VERSION 5.7 ;
BUSBITCHARS "[]" ;
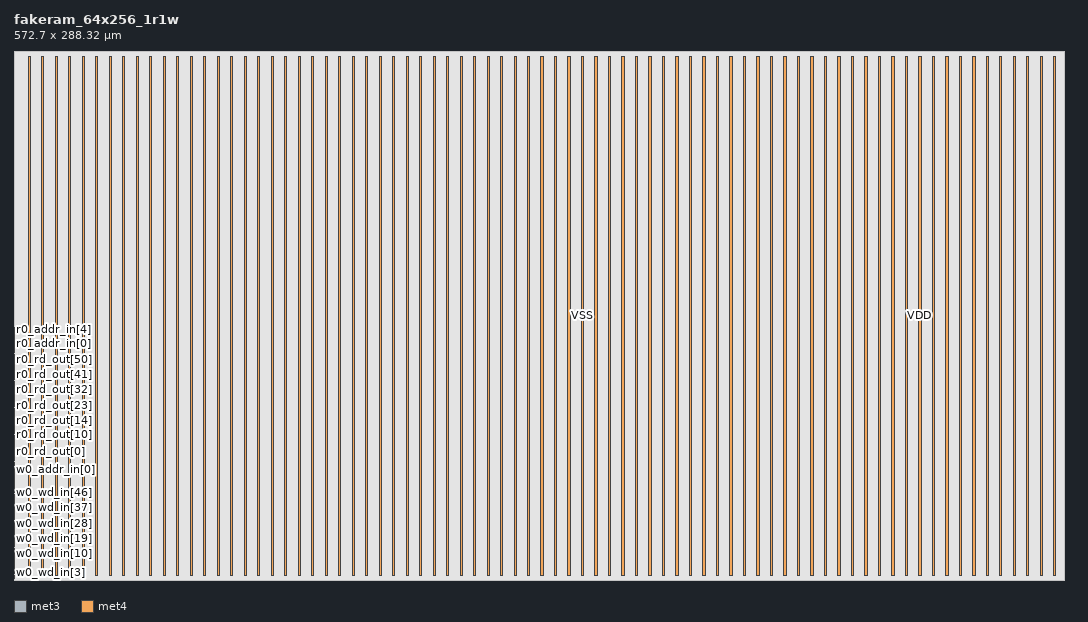
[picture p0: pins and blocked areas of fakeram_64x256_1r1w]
MACRO fakeram_64x256_1r1w
  FOREIGN fakeram_64x256_1r1w 0 0 ;
  SYMMETRY X Y R90 ;
  SIZE 572.700 BY 288.320 ;
  CLASS BLOCK ;
  PIN w0_wd_in[0]
    DIRECTION INPUT ;
    USE SIGNAL ;
    SHAPE ABUTMENT ;
    PORT
      LAYER met3 ;
      RECT 0.000 0.920 0.500 1.420 ;
    END
  END w0_wd_in[0]
  PIN w0_wd_in[1]
    DIRECTION INPUT ;
    USE SIGNAL ;
    SHAPE ABUTMENT ;
    PORT
      LAYER met3 ;
      RECT 0.000 1.840 0.500 2.340 ;
    END
  END w0_wd_in[1]
  PIN w0_wd_in[2]
    DIRECTION INPUT ;
    USE SIGNAL ;
    SHAPE ABUTMENT ;
    PORT
      LAYER met3 ;
      RECT 0.000 2.760 0.500 3.260 ;
    END
  END w0_wd_in[2]
  PIN w0_wd_in[3]
    DIRECTION INPUT ;
    USE SIGNAL ;
    SHAPE ABUTMENT ;
    PORT
      LAYER met3 ;
      RECT 0.000 3.680 0.500 4.180 ;
    END
  END w0_wd_in[3]
  PIN w0_wd_in[4]
    DIRECTION INPUT ;
    USE SIGNAL ;
    SHAPE ABUTMENT ;
    PORT
      LAYER met3 ;
      RECT 0.000 4.600 0.500 5.100 ;
    END
  END w0_wd_in[4]
  PIN w0_wd_in[5]
    DIRECTION INPUT ;
    USE SIGNAL ;
    SHAPE ABUTMENT ;
    PORT
      LAYER met3 ;
      RECT 0.000 5.520 0.500 6.020 ;
    END
  END w0_wd_in[5]
  PIN w0_wd_in[6]
    DIRECTION INPUT ;
    USE SIGNAL ;
    SHAPE ABUTMENT ;
    PORT
      LAYER met3 ;
      RECT 0.000 6.440 0.500 6.940 ;
    END
  END w0_wd_in[6]
  PIN w0_wd_in[7]
    DIRECTION INPUT ;
    USE SIGNAL ;
    SHAPE ABUTMENT ;
    PORT
      LAYER met3 ;
      RECT 0.000 7.360 0.500 7.860 ;
    END
  END w0_wd_in[7]
  PIN w0_wd_in[8]
    DIRECTION INPUT ;
    USE SIGNAL ;
    SHAPE ABUTMENT ;
    PORT
      LAYER met3 ;
      RECT 0.000 8.280 0.500 8.780 ;
    END
  END w0_wd_in[8]
  PIN w0_wd_in[9]
    DIRECTION INPUT ;
    USE SIGNAL ;
    SHAPE ABUTMENT ;
    PORT
      LAYER met3 ;
      RECT 0.000 9.200 0.500 9.700 ;
    END
  END w0_wd_in[9]
  PIN w0_wd_in[10]
    DIRECTION INPUT ;
    USE SIGNAL ;
    SHAPE ABUTMENT ;
    PORT
      LAYER met3 ;
      RECT 0.000 10.120 0.500 10.620 ;
    END
  END w0_wd_in[10]
  PIN w0_wd_in[11]
    DIRECTION INPUT ;
    USE SIGNAL ;
    SHAPE ABUTMENT ;
    PORT
      LAYER met3 ;
      RECT 0.000 11.040 0.500 11.540 ;
    END
  END w0_wd_in[11]
  PIN w0_wd_in[12]
    DIRECTION INPUT ;
    USE SIGNAL ;
    SHAPE ABUTMENT ;
    PORT
      LAYER met3 ;
      RECT 0.000 11.960 0.500 12.460 ;
    END
  END w0_wd_in[12]
  PIN w0_wd_in[13]
    DIRECTION INPUT ;
    USE SIGNAL ;
    SHAPE ABUTMENT ;
    PORT
      LAYER met3 ;
      RECT 0.000 12.880 0.500 13.380 ;
    END
  END w0_wd_in[13]
  PIN w0_wd_in[14]
    DIRECTION INPUT ;
    USE SIGNAL ;
    SHAPE ABUTMENT ;
    PORT
      LAYER met3 ;
      RECT 0.000 13.800 0.500 14.300 ;
    END
  END w0_wd_in[14]
  PIN w0_wd_in[15]
    DIRECTION INPUT ;
    USE SIGNAL ;
    SHAPE ABUTMENT ;
    PORT
      LAYER met3 ;
      RECT 0.000 14.720 0.500 15.220 ;
    END
  END w0_wd_in[15]
  PIN w0_wd_in[16]
    DIRECTION INPUT ;
    USE SIGNAL ;
    SHAPE ABUTMENT ;
    PORT
      LAYER met3 ;
      RECT 0.000 15.640 0.500 16.140 ;
    END
  END w0_wd_in[16]
  PIN w0_wd_in[17]
    DIRECTION INPUT ;
    USE SIGNAL ;
    SHAPE ABUTMENT ;
    PORT
      LAYER met3 ;
      RECT 0.000 16.560 0.500 17.060 ;
    END
  END w0_wd_in[17]
  PIN w0_wd_in[18]
    DIRECTION INPUT ;
    USE SIGNAL ;
    SHAPE ABUTMENT ;
    PORT
      LAYER met3 ;
      RECT 0.000 17.480 0.500 17.980 ;
    END
  END w0_wd_in[18]
  PIN w0_wd_in[19]
    DIRECTION INPUT ;
    USE SIGNAL ;
    SHAPE ABUTMENT ;
    PORT
      LAYER met3 ;
      RECT 0.000 18.400 0.500 18.900 ;
    END
  END w0_wd_in[19]
  PIN w0_wd_in[20]
    DIRECTION INPUT ;
    USE SIGNAL ;
    SHAPE ABUTMENT ;
    PORT
      LAYER met3 ;
      RECT 0.000 19.320 0.500 19.820 ;
    END
  END w0_wd_in[20]
  PIN w0_wd_in[21]
    DIRECTION INPUT ;
    USE SIGNAL ;
    SHAPE ABUTMENT ;
    PORT
      LAYER met3 ;
      RECT 0.000 20.240 0.500 20.740 ;
    END
  END w0_wd_in[21]
  PIN w0_wd_in[22]
    DIRECTION INPUT ;
    USE SIGNAL ;
    SHAPE ABUTMENT ;
    PORT
      LAYER met3 ;
      RECT 0.000 21.160 0.500 21.660 ;
    END
  END w0_wd_in[22]
  PIN w0_wd_in[23]
    DIRECTION INPUT ;
    USE SIGNAL ;
    SHAPE ABUTMENT ;
    PORT
      LAYER met3 ;
      RECT 0.000 22.080 0.500 22.580 ;
    END
  END w0_wd_in[23]
  PIN w0_wd_in[24]
    DIRECTION INPUT ;
    USE SIGNAL ;
    SHAPE ABUTMENT ;
    PORT
      LAYER met3 ;
      RECT 0.000 23.000 0.500 23.500 ;
    END
  END w0_wd_in[24]
  PIN w0_wd_in[25]
    DIRECTION INPUT ;
    USE SIGNAL ;
    SHAPE ABUTMENT ;
    PORT
      LAYER met3 ;
      RECT 0.000 23.920 0.500 24.420 ;
    END
  END w0_wd_in[25]
  PIN w0_wd_in[26]
    DIRECTION INPUT ;
    USE SIGNAL ;
    SHAPE ABUTMENT ;
    PORT
      LAYER met3 ;
      RECT 0.000 24.840 0.500 25.340 ;
    END
  END w0_wd_in[26]
  PIN w0_wd_in[27]
    DIRECTION INPUT ;
    USE SIGNAL ;
    SHAPE ABUTMENT ;
    PORT
      LAYER met3 ;
      RECT 0.000 25.760 0.500 26.260 ;
    END
  END w0_wd_in[27]
  PIN w0_wd_in[28]
    DIRECTION INPUT ;
    USE SIGNAL ;
    SHAPE ABUTMENT ;
    PORT
      LAYER met3 ;
      RECT 0.000 26.680 0.500 27.180 ;
    END
  END w0_wd_in[28]
  PIN w0_wd_in[29]
    DIRECTION INPUT ;
    USE SIGNAL ;
    SHAPE ABUTMENT ;
    PORT
      LAYER met3 ;
      RECT 0.000 27.600 0.500 28.100 ;
    END
  END w0_wd_in[29]
  PIN w0_wd_in[30]
    DIRECTION INPUT ;
    USE SIGNAL ;
    SHAPE ABUTMENT ;
    PORT
      LAYER met3 ;
      RECT 0.000 28.520 0.500 29.020 ;
    END
  END w0_wd_in[30]
  PIN w0_wd_in[31]
    DIRECTION INPUT ;
    USE SIGNAL ;
    SHAPE ABUTMENT ;
    PORT
      LAYER met3 ;
      RECT 0.000 29.440 0.500 29.940 ;
    END
  END w0_wd_in[31]
  PIN w0_wd_in[32]
    DIRECTION INPUT ;
    USE SIGNAL ;
    SHAPE ABUTMENT ;
    PORT
      LAYER met3 ;
      RECT 0.000 30.360 0.500 30.860 ;
    END
  END w0_wd_in[32]
  PIN w0_wd_in[33]
    DIRECTION INPUT ;
    USE SIGNAL ;
    SHAPE ABUTMENT ;
    PORT
      LAYER met3 ;
      RECT 0.000 31.280 0.500 31.780 ;
    END
  END w0_wd_in[33]
  PIN w0_wd_in[34]
    DIRECTION INPUT ;
    USE SIGNAL ;
    SHAPE ABUTMENT ;
    PORT
      LAYER met3 ;
      RECT 0.000 32.200 0.500 32.700 ;
    END
  END w0_wd_in[34]
  PIN w0_wd_in[35]
    DIRECTION INPUT ;
    USE SIGNAL ;
    SHAPE ABUTMENT ;
    PORT
      LAYER met3 ;
      RECT 0.000 33.120 0.500 33.620 ;
    END
  END w0_wd_in[35]
  PIN w0_wd_in[36]
    DIRECTION INPUT ;
    USE SIGNAL ;
    SHAPE ABUTMENT ;
    PORT
      LAYER met3 ;
      RECT 0.000 34.040 0.500 34.540 ;
    END
  END w0_wd_in[36]
  PIN w0_wd_in[37]
    DIRECTION INPUT ;
    USE SIGNAL ;
    SHAPE ABUTMENT ;
    PORT
      LAYER met3 ;
      RECT 0.000 34.960 0.500 35.460 ;
    END
  END w0_wd_in[37]
  PIN w0_wd_in[38]
    DIRECTION INPUT ;
    USE SIGNAL ;
    SHAPE ABUTMENT ;
    PORT
      LAYER met3 ;
      RECT 0.000 35.880 0.500 36.380 ;
    END
  END w0_wd_in[38]
  PIN w0_wd_in[39]
    DIRECTION INPUT ;
    USE SIGNAL ;
    SHAPE ABUTMENT ;
    PORT
      LAYER met3 ;
      RECT 0.000 36.800 0.500 37.300 ;
    END
  END w0_wd_in[39]
  PIN w0_wd_in[40]
    DIRECTION INPUT ;
    USE SIGNAL ;
    SHAPE ABUTMENT ;
    PORT
      LAYER met3 ;
      RECT 0.000 37.720 0.500 38.220 ;
    END
  END w0_wd_in[40]
  PIN w0_wd_in[41]
    DIRECTION INPUT ;
    USE SIGNAL ;
    SHAPE ABUTMENT ;
    PORT
      LAYER met3 ;
      RECT 0.000 38.640 0.500 39.140 ;
    END
  END w0_wd_in[41]
  PIN w0_wd_in[42]
    DIRECTION INPUT ;
    USE SIGNAL ;
    SHAPE ABUTMENT ;
    PORT
      LAYER met3 ;
      RECT 0.000 39.560 0.500 40.060 ;
    END
  END w0_wd_in[42]
  PIN w0_wd_in[43]
    DIRECTION INPUT ;
    USE SIGNAL ;
    SHAPE ABUTMENT ;
    PORT
      LAYER met3 ;
      RECT 0.000 40.480 0.500 40.980 ;
    END
  END w0_wd_in[43]
  PIN w0_wd_in[44]
    DIRECTION INPUT ;
    USE SIGNAL ;
    SHAPE ABUTMENT ;
    PORT
      LAYER met3 ;
      RECT 0.000 41.400 0.500 41.900 ;
    END
  END w0_wd_in[44]
  PIN w0_wd_in[45]
    DIRECTION INPUT ;
    USE SIGNAL ;
    SHAPE ABUTMENT ;
    PORT
      LAYER met3 ;
      RECT 0.000 42.320 0.500 42.820 ;
    END
  END w0_wd_in[45]
  PIN w0_wd_in[46]
    DIRECTION INPUT ;
    USE SIGNAL ;
    SHAPE ABUTMENT ;
    PORT
      LAYER met3 ;
      RECT 0.000 43.240 0.500 43.740 ;
    END
  END w0_wd_in[46]
  PIN w0_wd_in[47]
    DIRECTION INPUT ;
    USE SIGNAL ;
    SHAPE ABUTMENT ;
    PORT
      LAYER met3 ;
      RECT 0.000 44.160 0.500 44.660 ;
    END
  END w0_wd_in[47]
  PIN w0_wd_in[48]
    DIRECTION INPUT ;
    USE SIGNAL ;
    SHAPE ABUTMENT ;
    PORT
      LAYER met3 ;
      RECT 0.000 45.080 0.500 45.580 ;
    END
  END w0_wd_in[48]
  PIN w0_wd_in[49]
    DIRECTION INPUT ;
    USE SIGNAL ;
    SHAPE ABUTMENT ;
    PORT
      LAYER met3 ;
      RECT 0.000 46.000 0.500 46.500 ;
    END
  END w0_wd_in[49]
  PIN w0_wd_in[50]
    DIRECTION INPUT ;
    USE SIGNAL ;
    SHAPE ABUTMENT ;
    PORT
      LAYER met3 ;
      RECT 0.000 46.920 0.500 47.420 ;
    END
  END w0_wd_in[50]
  PIN w0_wd_in[51]
    DIRECTION INPUT ;
    USE SIGNAL ;
    SHAPE ABUTMENT ;
    PORT
      LAYER met3 ;
      RECT 0.000 47.840 0.500 48.340 ;
    END
  END w0_wd_in[51]
  PIN w0_wd_in[52]
    DIRECTION INPUT ;
    USE SIGNAL ;
    SHAPE ABUTMENT ;
    PORT
      LAYER met3 ;
      RECT 0.000 48.760 0.500 49.260 ;
    END
  END w0_wd_in[52]
  PIN w0_wd_in[53]
    DIRECTION INPUT ;
    USE SIGNAL ;
    SHAPE ABUTMENT ;
    PORT
      LAYER met3 ;
      RECT 0.000 49.680 0.500 50.180 ;
    END
  END w0_wd_in[53]
  PIN w0_wd_in[54]
    DIRECTION INPUT ;
    USE SIGNAL ;
    SHAPE ABUTMENT ;
    PORT
      LAYER met3 ;
      RECT 0.000 50.600 0.500 51.100 ;
    END
  END w0_wd_in[54]
  PIN w0_wd_in[55]
    DIRECTION INPUT ;
    USE SIGNAL ;
    SHAPE ABUTMENT ;
    PORT
      LAYER met3 ;
      RECT 0.000 51.520 0.500 52.020 ;
    END
  END w0_wd_in[55]
  PIN w0_wd_in[56]
    DIRECTION INPUT ;
    USE SIGNAL ;
    SHAPE ABUTMENT ;
    PORT
      LAYER met3 ;
      RECT 0.000 52.440 0.500 52.940 ;
    END
  END w0_wd_in[56]
  PIN w0_wd_in[57]
    DIRECTION INPUT ;
    USE SIGNAL ;
    SHAPE ABUTMENT ;
    PORT
      LAYER met3 ;
      RECT 0.000 53.360 0.500 53.860 ;
    END
  END w0_wd_in[57]
  PIN w0_wd_in[58]
    DIRECTION INPUT ;
    USE SIGNAL ;
    SHAPE ABUTMENT ;
    PORT
      LAYER met3 ;
      RECT 0.000 54.280 0.500 54.780 ;
    END
  END w0_wd_in[58]
  PIN w0_wd_in[59]
    DIRECTION INPUT ;
    USE SIGNAL ;
    SHAPE ABUTMENT ;
    PORT
      LAYER met3 ;
      RECT 0.000 55.200 0.500 55.700 ;
    END
  END w0_wd_in[59]
  PIN w0_wd_in[60]
    DIRECTION INPUT ;
    USE SIGNAL ;
    SHAPE ABUTMENT ;
    PORT
      LAYER met3 ;
      RECT 0.000 56.120 0.500 56.620 ;
    END
  END w0_wd_in[60]
  PIN w0_wd_in[61]
    DIRECTION INPUT ;
    USE SIGNAL ;
    SHAPE ABUTMENT ;
    PORT
      LAYER met3 ;
      RECT 0.000 57.040 0.500 57.540 ;
    END
  END w0_wd_in[61]
  PIN w0_wd_in[62]
    DIRECTION INPUT ;
    USE SIGNAL ;
    SHAPE ABUTMENT ;
    PORT
      LAYER met3 ;
      RECT 0.000 57.960 0.500 58.460 ;
    END
  END w0_wd_in[62]
  PIN w0_wd_in[63]
    DIRECTION INPUT ;
    USE SIGNAL ;
    SHAPE ABUTMENT ;
    PORT
      LAYER met3 ;
      RECT 0.000 58.880 0.500 59.380 ;
    END
  END w0_wd_in[63]
  PIN w0_addr_in[0]
    DIRECTION INPUT ;
    USE SIGNAL ;
    SHAPE ABUTMENT ;
    PORT
      LAYER met3 ;
      RECT 0.000 59.800 0.500 60.300 ;
    END
  END w0_addr_in[0]
  PIN w0_addr_in[1]
    DIRECTION INPUT ;
    USE SIGNAL ;
    SHAPE ABUTMENT ;
    PORT
      LAYER met3 ;
      RECT 0.000 60.720 0.500 61.220 ;
    END
  END w0_addr_in[1]
  PIN w0_addr_in[2]
    DIRECTION INPUT ;
    USE SIGNAL ;
    SHAPE ABUTMENT ;
    PORT
      LAYER met3 ;
      RECT 0.000 61.640 0.500 62.140 ;
    END
  END w0_addr_in[2]
  PIN w0_addr_in[3]
    DIRECTION INPUT ;
    USE SIGNAL ;
    SHAPE ABUTMENT ;
    PORT
      LAYER met3 ;
      RECT 0.000 62.560 0.500 63.060 ;
    END
  END w0_addr_in[3]
  PIN w0_addr_in[4]
    DIRECTION INPUT ;
    USE SIGNAL ;
    SHAPE ABUTMENT ;
    PORT
      LAYER met3 ;
      RECT 0.000 63.480 0.500 63.980 ;
    END
  END w0_addr_in[4]
  PIN w0_addr_in[5]
    DIRECTION INPUT ;
    USE SIGNAL ;
    SHAPE ABUTMENT ;
    PORT
      LAYER met3 ;
      RECT 0.000 64.400 0.500 64.900 ;
    END
  END w0_addr_in[5]
  PIN w0_addr_in[6]
    DIRECTION INPUT ;
    USE SIGNAL ;
    SHAPE ABUTMENT ;
    PORT
      LAYER met3 ;
      RECT 0.000 65.320 0.500 65.820 ;
    END
  END w0_addr_in[6]
  PIN w0_addr_in[7]
    DIRECTION INPUT ;
    USE SIGNAL ;
    SHAPE ABUTMENT ;
    PORT
      LAYER met3 ;
      RECT 0.000 66.240 0.500 66.740 ;
    END
  END w0_addr_in[7]
  PIN w0_clk
    DIRECTION INPUT ;
    USE SIGNAL ;
    SHAPE ABUTMENT ;
    PORT
      LAYER met3 ;
      RECT 0.000 67.160 0.500 67.660 ;
    END
  END w0_clk
  PIN w0_ce_in
    DIRECTION INPUT ;
    USE SIGNAL ;
    SHAPE ABUTMENT ;
    PORT
      LAYER met3 ;
      RECT 0.000 68.080 0.500 68.580 ;
    END
  END w0_ce_in
  PIN w0_we_in
    DIRECTION INPUT ;
    USE SIGNAL ;
    SHAPE ABUTMENT ;
    PORT
      LAYER met3 ;
      RECT 0.000 69.000 0.500 69.500 ;
    END
  END w0_we_in
  PIN r0_rd_out[0]
    DIRECTION OUTPUT ;
    USE SIGNAL ;
    SHAPE ABUTMENT ;
    PORT
      LAYER met3 ;
      RECT 0.000 69.920 0.500 70.420 ;
    END
  END r0_rd_out[0]
  PIN r0_rd_out[1]
    DIRECTION OUTPUT ;
    USE SIGNAL ;
    SHAPE ABUTMENT ;
    PORT
      LAYER met3 ;
      RECT 0.000 70.840 0.500 71.340 ;
    END
  END r0_rd_out[1]
  PIN r0_rd_out[2]
    DIRECTION OUTPUT ;
    USE SIGNAL ;
    SHAPE ABUTMENT ;
    PORT
      LAYER met3 ;
      RECT 0.000 71.760 0.500 72.260 ;
    END
  END r0_rd_out[2]
  PIN r0_rd_out[3]
    DIRECTION OUTPUT ;
    USE SIGNAL ;
    SHAPE ABUTMENT ;
    PORT
      LAYER met3 ;
      RECT 0.000 72.680 0.500 73.180 ;
    END
  END r0_rd_out[3]
  PIN r0_rd_out[4]
    DIRECTION OUTPUT ;
    USE SIGNAL ;
    SHAPE ABUTMENT ;
    PORT
      LAYER met3 ;
      RECT 0.000 73.600 0.500 74.100 ;
    END
  END r0_rd_out[4]
  PIN r0_rd_out[5]
    DIRECTION OUTPUT ;
    USE SIGNAL ;
    SHAPE ABUTMENT ;
    PORT
      LAYER met3 ;
      RECT 0.000 74.520 0.500 75.020 ;
    END
  END r0_rd_out[5]
  PIN r0_rd_out[6]
    DIRECTION OUTPUT ;
    USE SIGNAL ;
    SHAPE ABUTMENT ;
    PORT
      LAYER met3 ;
      RECT 0.000 75.440 0.500 75.940 ;
    END
  END r0_rd_out[6]
  PIN r0_rd_out[7]
    DIRECTION OUTPUT ;
    USE SIGNAL ;
    SHAPE ABUTMENT ;
    PORT
      LAYER met3 ;
      RECT 0.000 76.360 0.500 76.860 ;
    END
  END r0_rd_out[7]
  PIN r0_rd_out[8]
    DIRECTION OUTPUT ;
    USE SIGNAL ;
    SHAPE ABUTMENT ;
    PORT
      LAYER met3 ;
      RECT 0.000 77.280 0.500 77.780 ;
    END
  END r0_rd_out[8]
  PIN r0_rd_out[9]
    DIRECTION OUTPUT ;
    USE SIGNAL ;
    SHAPE ABUTMENT ;
    PORT
      LAYER met3 ;
      RECT 0.000 78.200 0.500 78.700 ;
    END
  END r0_rd_out[9]
  PIN r0_rd_out[10]
    DIRECTION OUTPUT ;
    USE SIGNAL ;
    SHAPE ABUTMENT ;
    PORT
      LAYER met3 ;
      RECT 0.000 79.120 0.500 79.620 ;
    END
  END r0_rd_out[10]
  PIN r0_rd_out[11]
    DIRECTION OUTPUT ;
    USE SIGNAL ;
    SHAPE ABUTMENT ;
    PORT
      LAYER met3 ;
      RECT 0.000 80.040 0.500 80.540 ;
    END
  END r0_rd_out[11]
  PIN r0_rd_out[12]
    DIRECTION OUTPUT ;
    USE SIGNAL ;
    SHAPE ABUTMENT ;
    PORT
      LAYER met3 ;
      RECT 0.000 80.960 0.500 81.460 ;
    END
  END r0_rd_out[12]
  PIN r0_rd_out[13]
    DIRECTION OUTPUT ;
    USE SIGNAL ;
    SHAPE ABUTMENT ;
    PORT
      LAYER met3 ;
      RECT 0.000 81.880 0.500 82.380 ;
    END
  END r0_rd_out[13]
  PIN r0_rd_out[14]
    DIRECTION OUTPUT ;
    USE SIGNAL ;
    SHAPE ABUTMENT ;
    PORT
      LAYER met3 ;
      RECT 0.000 82.800 0.500 83.300 ;
    END
  END r0_rd_out[14]
  PIN r0_rd_out[15]
    DIRECTION OUTPUT ;
    USE SIGNAL ;
    SHAPE ABUTMENT ;
    PORT
      LAYER met3 ;
      RECT 0.000 83.720 0.500 84.220 ;
    END
  END r0_rd_out[15]
  PIN r0_rd_out[16]
    DIRECTION OUTPUT ;
    USE SIGNAL ;
    SHAPE ABUTMENT ;
    PORT
      LAYER met3 ;
      RECT 0.000 84.640 0.500 85.140 ;
    END
  END r0_rd_out[16]
  PIN r0_rd_out[17]
    DIRECTION OUTPUT ;
    USE SIGNAL ;
    SHAPE ABUTMENT ;
    PORT
      LAYER met3 ;
      RECT 0.000 85.560 0.500 86.060 ;
    END
  END r0_rd_out[17]
  PIN r0_rd_out[18]
    DIRECTION OUTPUT ;
    USE SIGNAL ;
    SHAPE ABUTMENT ;
    PORT
      LAYER met3 ;
      RECT 0.000 86.480 0.500 86.980 ;
    END
  END r0_rd_out[18]
  PIN r0_rd_out[19]
    DIRECTION OUTPUT ;
    USE SIGNAL ;
    SHAPE ABUTMENT ;
    PORT
      LAYER met3 ;
      RECT 0.000 87.400 0.500 87.900 ;
    END
  END r0_rd_out[19]
  PIN r0_rd_out[20]
    DIRECTION OUTPUT ;
    USE SIGNAL ;
    SHAPE ABUTMENT ;
    PORT
      LAYER met3 ;
      RECT 0.000 88.320 0.500 88.820 ;
    END
  END r0_rd_out[20]
  PIN r0_rd_out[21]
    DIRECTION OUTPUT ;
    USE SIGNAL ;
    SHAPE ABUTMENT ;
    PORT
      LAYER met3 ;
      RECT 0.000 89.240 0.500 89.740 ;
    END
  END r0_rd_out[21]
  PIN r0_rd_out[22]
    DIRECTION OUTPUT ;
    USE SIGNAL ;
    SHAPE ABUTMENT ;
    PORT
      LAYER met3 ;
      RECT 0.000 90.160 0.500 90.660 ;
    END
  END r0_rd_out[22]
  PIN r0_rd_out[23]
    DIRECTION OUTPUT ;
    USE SIGNAL ;
    SHAPE ABUTMENT ;
    PORT
      LAYER met3 ;
      RECT 0.000 91.080 0.500 91.580 ;
    END
  END r0_rd_out[23]
  PIN r0_rd_out[24]
    DIRECTION OUTPUT ;
    USE SIGNAL ;
    SHAPE ABUTMENT ;
    PORT
      LAYER met3 ;
      RECT 0.000 92.000 0.500 92.500 ;
    END
  END r0_rd_out[24]
  PIN r0_rd_out[25]
    DIRECTION OUTPUT ;
    USE SIGNAL ;
    SHAPE ABUTMENT ;
    PORT
      LAYER met3 ;
      RECT 0.000 92.920 0.500 93.420 ;
    END
  END r0_rd_out[25]
  PIN r0_rd_out[26]
    DIRECTION OUTPUT ;
    USE SIGNAL ;
    SHAPE ABUTMENT ;
    PORT
      LAYER met3 ;
      RECT 0.000 93.840 0.500 94.340 ;
    END
  END r0_rd_out[26]
  PIN r0_rd_out[27]
    DIRECTION OUTPUT ;
    USE SIGNAL ;
    SHAPE ABUTMENT ;
    PORT
      LAYER met3 ;
      RECT 0.000 94.760 0.500 95.260 ;
    END
  END r0_rd_out[27]
  PIN r0_rd_out[28]
    DIRECTION OUTPUT ;
    USE SIGNAL ;
    SHAPE ABUTMENT ;
    PORT
      LAYER met3 ;
      RECT 0.000 95.680 0.500 96.180 ;
    END
  END r0_rd_out[28]
  PIN r0_rd_out[29]
    DIRECTION OUTPUT ;
    USE SIGNAL ;
    SHAPE ABUTMENT ;
    PORT
      LAYER met3 ;
      RECT 0.000 96.600 0.500 97.100 ;
    END
  END r0_rd_out[29]
  PIN r0_rd_out[30]
    DIRECTION OUTPUT ;
    USE SIGNAL ;
    SHAPE ABUTMENT ;
    PORT
      LAYER met3 ;
      RECT 0.000 97.520 0.500 98.020 ;
    END
  END r0_rd_out[30]
  PIN r0_rd_out[31]
    DIRECTION OUTPUT ;
    USE SIGNAL ;
    SHAPE ABUTMENT ;
    PORT
      LAYER met3 ;
      RECT 0.000 98.440 0.500 98.940 ;
    END
  END r0_rd_out[31]
  PIN r0_rd_out[32]
    DIRECTION OUTPUT ;
    USE SIGNAL ;
    SHAPE ABUTMENT ;
    PORT
      LAYER met3 ;
      RECT 0.000 99.360 0.500 99.860 ;
    END
  END r0_rd_out[32]
  PIN r0_rd_out[33]
    DIRECTION OUTPUT ;
    USE SIGNAL ;
    SHAPE ABUTMENT ;
    PORT
      LAYER met3 ;
      RECT 0.000 100.280 0.500 100.780 ;
    END
  END r0_rd_out[33]
  PIN r0_rd_out[34]
    DIRECTION OUTPUT ;
    USE SIGNAL ;
    SHAPE ABUTMENT ;
    PORT
      LAYER met3 ;
      RECT 0.000 101.200 0.500 101.700 ;
    END
  END r0_rd_out[34]
  PIN r0_rd_out[35]
    DIRECTION OUTPUT ;
    USE SIGNAL ;
    SHAPE ABUTMENT ;
    PORT
      LAYER met3 ;
      RECT 0.000 102.120 0.500 102.620 ;
    END
  END r0_rd_out[35]
  PIN r0_rd_out[36]
    DIRECTION OUTPUT ;
    USE SIGNAL ;
    SHAPE ABUTMENT ;
    PORT
      LAYER met3 ;
      RECT 0.000 103.040 0.500 103.540 ;
    END
  END r0_rd_out[36]
  PIN r0_rd_out[37]
    DIRECTION OUTPUT ;
    USE SIGNAL ;
    SHAPE ABUTMENT ;
    PORT
      LAYER met3 ;
      RECT 0.000 103.960 0.500 104.460 ;
    END
  END r0_rd_out[37]
  PIN r0_rd_out[38]
    DIRECTION OUTPUT ;
    USE SIGNAL ;
    SHAPE ABUTMENT ;
    PORT
      LAYER met3 ;
      RECT 0.000 104.880 0.500 105.380 ;
    END
  END r0_rd_out[38]
  PIN r0_rd_out[39]
    DIRECTION OUTPUT ;
    USE SIGNAL ;
    SHAPE ABUTMENT ;
    PORT
      LAYER met3 ;
      RECT 0.000 105.800 0.500 106.300 ;
    END
  END r0_rd_out[39]
  PIN r0_rd_out[40]
    DIRECTION OUTPUT ;
    USE SIGNAL ;
    SHAPE ABUTMENT ;
    PORT
      LAYER met3 ;
      RECT 0.000 106.720 0.500 107.220 ;
    END
  END r0_rd_out[40]
  PIN r0_rd_out[41]
    DIRECTION OUTPUT ;
    USE SIGNAL ;
    SHAPE ABUTMENT ;
    PORT
      LAYER met3 ;
      RECT 0.000 107.640 0.500 108.140 ;
    END
  END r0_rd_out[41]
  PIN r0_rd_out[42]
    DIRECTION OUTPUT ;
    USE SIGNAL ;
    SHAPE ABUTMENT ;
    PORT
      LAYER met3 ;
      RECT 0.000 108.560 0.500 109.060 ;
    END
  END r0_rd_out[42]
  PIN r0_rd_out[43]
    DIRECTION OUTPUT ;
    USE SIGNAL ;
    SHAPE ABUTMENT ;
    PORT
      LAYER met3 ;
      RECT 0.000 109.480 0.500 109.980 ;
    END
  END r0_rd_out[43]
  PIN r0_rd_out[44]
    DIRECTION OUTPUT ;
    USE SIGNAL ;
    SHAPE ABUTMENT ;
    PORT
      LAYER met3 ;
      RECT 0.000 110.400 0.500 110.900 ;
    END
  END r0_rd_out[44]
  PIN r0_rd_out[45]
    DIRECTION OUTPUT ;
    USE SIGNAL ;
    SHAPE ABUTMENT ;
    PORT
      LAYER met3 ;
      RECT 0.000 111.320 0.500 111.820 ;
    END
  END r0_rd_out[45]
  PIN r0_rd_out[46]
    DIRECTION OUTPUT ;
    USE SIGNAL ;
    SHAPE ABUTMENT ;
    PORT
      LAYER met3 ;
      RECT 0.000 112.240 0.500 112.740 ;
    END
  END r0_rd_out[46]
  PIN r0_rd_out[47]
    DIRECTION OUTPUT ;
    USE SIGNAL ;
    SHAPE ABUTMENT ;
    PORT
      LAYER met3 ;
      RECT 0.000 113.160 0.500 113.660 ;
    END
  END r0_rd_out[47]
  PIN r0_rd_out[48]
    DIRECTION OUTPUT ;
    USE SIGNAL ;
    SHAPE ABUTMENT ;
    PORT
      LAYER met3 ;
      RECT 0.000 114.080 0.500 114.580 ;
    END
  END r0_rd_out[48]
  PIN r0_rd_out[49]
    DIRECTION OUTPUT ;
    USE SIGNAL ;
    SHAPE ABUTMENT ;
    PORT
      LAYER met3 ;
      RECT 0.000 115.000 0.500 115.500 ;
    END
  END r0_rd_out[49]
  PIN r0_rd_out[50]
    DIRECTION OUTPUT ;
    USE SIGNAL ;
    SHAPE ABUTMENT ;
    PORT
      LAYER met3 ;
      RECT 0.000 115.920 0.500 116.420 ;
    END
  END r0_rd_out[50]
  PIN r0_rd_out[51]
    DIRECTION OUTPUT ;
    USE SIGNAL ;
    SHAPE ABUTMENT ;
    PORT
      LAYER met3 ;
      RECT 0.000 116.840 0.500 117.340 ;
    END
  END r0_rd_out[51]
  PIN r0_rd_out[52]
    DIRECTION OUTPUT ;
    USE SIGNAL ;
    SHAPE ABUTMENT ;
    PORT
      LAYER met3 ;
      RECT 0.000 117.760 0.500 118.260 ;
    END
  END r0_rd_out[52]
  PIN r0_rd_out[53]
    DIRECTION OUTPUT ;
    USE SIGNAL ;
    SHAPE ABUTMENT ;
    PORT
      LAYER met3 ;
      RECT 0.000 118.680 0.500 119.180 ;
    END
  END r0_rd_out[53]
  PIN r0_rd_out[54]
    DIRECTION OUTPUT ;
    USE SIGNAL ;
    SHAPE ABUTMENT ;
    PORT
      LAYER met3 ;
      RECT 0.000 119.600 0.500 120.100 ;
    END
  END r0_rd_out[54]
  PIN r0_rd_out[55]
    DIRECTION OUTPUT ;
    USE SIGNAL ;
    SHAPE ABUTMENT ;
    PORT
      LAYER met3 ;
      RECT 0.000 120.520 0.500 121.020 ;
    END
  END r0_rd_out[55]
  PIN r0_rd_out[56]
    DIRECTION OUTPUT ;
    USE SIGNAL ;
    SHAPE ABUTMENT ;
    PORT
      LAYER met3 ;
      RECT 0.000 121.440 0.500 121.940 ;
    END
  END r0_rd_out[56]
  PIN r0_rd_out[57]
    DIRECTION OUTPUT ;
    USE SIGNAL ;
    SHAPE ABUTMENT ;
    PORT
      LAYER met3 ;
      RECT 0.000 122.360 0.500 122.860 ;
    END
  END r0_rd_out[57]
  PIN r0_rd_out[58]
    DIRECTION OUTPUT ;
    USE SIGNAL ;
    SHAPE ABUTMENT ;
    PORT
      LAYER met3 ;
      RECT 0.000 123.280 0.500 123.780 ;
    END
  END r0_rd_out[58]
  PIN r0_rd_out[59]
    DIRECTION OUTPUT ;
    USE SIGNAL ;
    SHAPE ABUTMENT ;
    PORT
      LAYER met3 ;
      RECT 0.000 124.200 0.500 124.700 ;
    END
  END r0_rd_out[59]
  PIN r0_rd_out[60]
    DIRECTION OUTPUT ;
    USE SIGNAL ;
    SHAPE ABUTMENT ;
    PORT
      LAYER met3 ;
      RECT 0.000 125.120 0.500 125.620 ;
    END
  END r0_rd_out[60]
  PIN r0_rd_out[61]
    DIRECTION OUTPUT ;
    USE SIGNAL ;
    SHAPE ABUTMENT ;
    PORT
      LAYER met3 ;
      RECT 0.000 126.040 0.500 126.540 ;
    END
  END r0_rd_out[61]
  PIN r0_rd_out[62]
    DIRECTION OUTPUT ;
    USE SIGNAL ;
    SHAPE ABUTMENT ;
    PORT
      LAYER met3 ;
      RECT 0.000 126.960 0.500 127.460 ;
    END
  END r0_rd_out[62]
  PIN r0_rd_out[63]
    DIRECTION OUTPUT ;
    USE SIGNAL ;
    SHAPE ABUTMENT ;
    PORT
      LAYER met3 ;
      RECT 0.000 127.880 0.500 128.380 ;
    END
  END r0_rd_out[63]
  PIN r0_addr_in[0]
    DIRECTION INPUT ;
    USE SIGNAL ;
    SHAPE ABUTMENT ;
    PORT
      LAYER met3 ;
      RECT 0.000 128.800 0.500 129.300 ;
    END
  END r0_addr_in[0]
  PIN r0_addr_in[1]
    DIRECTION INPUT ;
    USE SIGNAL ;
    SHAPE ABUTMENT ;
    PORT
      LAYER met3 ;
      RECT 0.000 129.720 0.500 130.220 ;
    END
  END r0_addr_in[1]
  PIN r0_addr_in[2]
    DIRECTION INPUT ;
    USE SIGNAL ;
    SHAPE ABUTMENT ;
    PORT
      LAYER met3 ;
      RECT 0.000 130.640 0.500 131.140 ;
    END
  END r0_addr_in[2]
  PIN r0_addr_in[3]
    DIRECTION INPUT ;
    USE SIGNAL ;
    SHAPE ABUTMENT ;
    PORT
      LAYER met3 ;
      RECT 0.000 131.560 0.500 132.060 ;
    END
  END r0_addr_in[3]
  PIN r0_addr_in[4]
    DIRECTION INPUT ;
    USE SIGNAL ;
    SHAPE ABUTMENT ;
    PORT
      LAYER met3 ;
      RECT 0.000 132.480 0.500 132.980 ;
    END
  END r0_addr_in[4]
  PIN r0_addr_in[5]
    DIRECTION INPUT ;
    USE SIGNAL ;
    SHAPE ABUTMENT ;
    PORT
      LAYER met3 ;
      RECT 0.000 133.400 0.500 133.900 ;
    END
  END r0_addr_in[5]
  PIN r0_addr_in[6]
    DIRECTION INPUT ;
    USE SIGNAL ;
    SHAPE ABUTMENT ;
    PORT
      LAYER met3 ;
      RECT 0.000 134.320 0.500 134.820 ;
    END
  END r0_addr_in[6]
  PIN r0_addr_in[7]
    DIRECTION INPUT ;
    USE SIGNAL ;
    SHAPE ABUTMENT ;
    PORT
      LAYER met3 ;
      RECT 0.000 135.240 0.500 135.740 ;
    END
  END r0_addr_in[7]
  PIN r0_clk
    DIRECTION INPUT ;
    USE SIGNAL ;
    SHAPE ABUTMENT ;
    PORT
      LAYER met3 ;
      RECT 0.000 136.160 0.500 136.660 ;
    END
  END r0_clk
  PIN r0_ce_in
    DIRECTION INPUT ;
    USE SIGNAL ;
    SHAPE ABUTMENT ;
    PORT
      LAYER met3 ;
      RECT 0.000 137.080 0.500 137.580 ;
    END
  END r0_ce_in
  PIN VDD
    DIRECTION INOUT ;
    USE POWER ;
    PORT
      LAYER met4 ;
      RECT 7.760 2.720 8.960 285.600 ;
      RECT 22.480 2.720 23.680 285.600 ;
      RECT 37.200 2.720 38.400 285.600 ;
      RECT 51.920 2.720 53.120 285.600 ;
      RECT 66.640 2.720 67.840 285.600 ;
      RECT 81.360 2.720 82.560 285.600 ;
      RECT 96.080 2.720 97.280 285.600 ;
      RECT 110.800 2.720 112.000 285.600 ;
      RECT 125.520 2.720 126.720 285.600 ;
      RECT 140.240 2.720 141.440 285.600 ;
      RECT 154.960 2.720 156.160 285.600 ;
      RECT 169.680 2.720 170.880 285.600 ;
      RECT 184.400 2.720 185.600 285.600 ;
      RECT 199.120 2.720 200.320 285.600 ;
      RECT 213.840 2.720 215.040 285.600 ;
      RECT 228.560 2.720 229.760 285.600 ;
      RECT 243.280 2.720 244.480 285.600 ;
      RECT 258.000 2.720 259.200 285.600 ;
      RECT 272.720 2.720 273.920 285.600 ;
      RECT 287.440 2.720 288.640 285.600 ;
      RECT 302.160 2.720 303.360 285.600 ;
      RECT 316.880 2.720 318.080 285.600 ;
      RECT 331.600 2.720 332.800 285.600 ;
      RECT 346.320 2.720 347.520 285.600 ;
      RECT 361.040 2.720 362.240 285.600 ;
      RECT 375.760 2.720 376.960 285.600 ;
      RECT 390.480 2.720 391.680 285.600 ;
      RECT 405.200 2.720 406.400 285.600 ;
      RECT 419.920 2.720 421.120 285.600 ;
      RECT 434.640 2.720 435.840 285.600 ;
      RECT 449.360 2.720 450.560 285.600 ;
      RECT 464.080 2.720 465.280 285.600 ;
      RECT 478.800 2.720 480.000 285.600 ;
      RECT 493.520 2.720 494.720 285.600 ;
      RECT 508.240 2.720 509.440 285.600 ;
      RECT 522.960 2.720 524.160 285.600 ;
      RECT 537.680 2.720 538.880 285.600 ;
      RECT 552.400 2.720 553.600 285.600 ;
      RECT 567.120 2.720 568.320 285.600 ;
    END
  END VDD
  PIN VSS
    DIRECTION INOUT ;
    USE GROUND ;
    PORT
      LAYER met4 ;
      RECT 15.120 2.720 16.320 285.600 ;
      RECT 29.840 2.720 31.040 285.600 ;
      RECT 44.560 2.720 45.760 285.600 ;
      RECT 59.280 2.720 60.480 285.600 ;
      RECT 74.000 2.720 75.200 285.600 ;
      RECT 88.720 2.720 89.920 285.600 ;
      RECT 103.440 2.720 104.640 285.600 ;
      RECT 118.160 2.720 119.360 285.600 ;
      RECT 132.880 2.720 134.080 285.600 ;
      RECT 147.600 2.720 148.800 285.600 ;
      RECT 162.320 2.720 163.520 285.600 ;
      RECT 177.040 2.720 178.240 285.600 ;
      RECT 191.760 2.720 192.960 285.600 ;
      RECT 206.480 2.720 207.680 285.600 ;
      RECT 221.200 2.720 222.400 285.600 ;
      RECT 235.920 2.720 237.120 285.600 ;
      RECT 250.640 2.720 251.840 285.600 ;
      RECT 265.360 2.720 266.560 285.600 ;
      RECT 280.080 2.720 281.280 285.600 ;
      RECT 294.800 2.720 296.000 285.600 ;
      RECT 309.520 2.720 310.720 285.600 ;
      RECT 324.240 2.720 325.440 285.600 ;
      RECT 338.960 2.720 340.160 285.600 ;
      RECT 353.680 2.720 354.880 285.600 ;
      RECT 368.400 2.720 369.600 285.600 ;
      RECT 383.120 2.720 384.320 285.600 ;
      RECT 397.840 2.720 399.040 285.600 ;
      RECT 412.560 2.720 413.760 285.600 ;
      RECT 427.280 2.720 428.480 285.600 ;
      RECT 442.000 2.720 443.200 285.600 ;
      RECT 456.720 2.720 457.920 285.600 ;
      RECT 471.440 2.720 472.640 285.600 ;
      RECT 486.160 2.720 487.360 285.600 ;
      RECT 500.880 2.720 502.080 285.600 ;
      RECT 515.600 2.720 516.800 285.600 ;
      RECT 530.320 2.720 531.520 285.600 ;
      RECT 545.040 2.720 546.240 285.600 ;
      RECT 559.760 2.720 560.960 285.600 ;
    END
  END VSS
  OBS
    LAYER met1 ;
      RECT 0.000 0.000 572.700 288.320 ;
    LAYER met2 ;
      RECT 0.000 0.000 572.700 288.320 ;
    LAYER met3 ;
      RECT 0.000 0.000 572.700 288.320 ;
  END
END fakeram_64x256_1r1w
END LIBRARY
